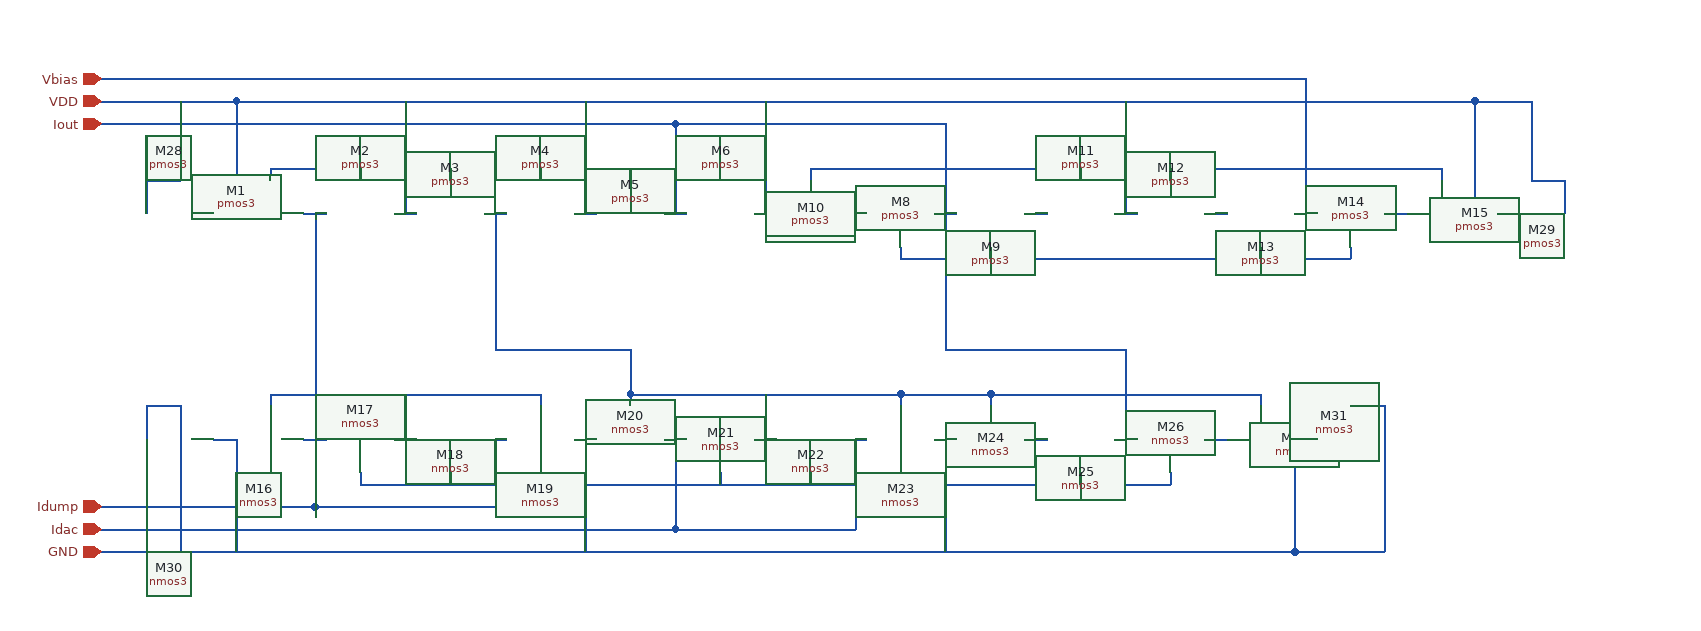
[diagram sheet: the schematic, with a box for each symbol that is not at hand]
v {xschem version=3.4.3 file_version=1.2
}
G {}
K {}
V {}
S {}
E {}
N 60 0 80 0 {
lab=#net1}
N 140 -0 160 -0 {
lab=VDD}
N 220 0 240 -0 {
lab=#net2}
N 300 0 320 0 {
lab=VDD}
N 380 -0 400 0 {
lab=Iout}
N 460 0 480 0 {
lab=VDD}
N 540 0 560 0 {
lab=#net3}
N 620 0 640 0 {
lab=Iout}
N 700 0 720 0 {
lab=#net4}
N 780 0 800 0 {
lab=VDD}
N 860 0 880 0 {
lab=#net5}
N 940 0 960 0 {
lab=VDD}
N 1020 0 1040 0 {
lab=#net6}
N 0 -100 0 0 {
lab=VDD}
N 1100 -100 1100 0 {
lab=VDD}
N 150 -100 150 -0 {
lab=VDD}
N 310 -100 310 -0 {
lab=VDD}
N 470 -100 470 0 {
lab=VDD}
N 790 -100 790 0 {
lab=VDD}
N -0 -100 1100 -100 {
lab=VDD}
N 30 -40 30 -30 {
lab=#net7}
N 510 -40 510 -30 {
lab=#net8}
N 430 -40 430 -30 {
lab=#net7}
N 350 -40 350 -30 {
lab=#net7}
N 270 -40 270 -30 {
lab=#net7}
N 190 -40 190 -30 {
lab=#net7}
N 110 -40 110 -30 {
lab=#net7}
N 590 30 590 40 {
lab=#net9}
N 590 40 990 40 {
lab=#net9}
N 990 30 990 40 {
lab=#net9}
N 910 30 910 40 {
lab=#net9}
N 670 30 670 40 {
lab=#net9}
N 830 -40 830 -30 {
lab=#net8}
N 30 -40 430 -40 {
lab=#net7}
N 1070 -40 1070 -30 {
lab=#net8}
N 750 -40 750 -30 {
lab=#net8}
N 510 -40 1070 -40 {
lab=#net8}
N 70 0 70 100 {
lab=#net1}
N 230 0 230 100 {
lab=#net2}
N 390 -80 390 -0 {
lab=Iout}
N 390 -80 630 -80 {
lab=Iout}
N 630 -80 630 0 {
lab=Iout}
N 950 -120 950 -0 {
lab=VDD}
N -20 -120 950 -120 {
lab=VDD}
N 30 160 30 170 {
lab=#net1}
N 30 160 270 160 {
lab=#net1}
N 270 160 270 170 {
lab=#net1}
N 140 200 160 200 {
lab=#net1}
N 150 160 150 200 {
lab=#net1}
N 70 100 70 160 {
lab=#net1}
N 60 200 80 200 {
lab=Idump}
N 220 200 240 200 {
lab=Idump}
N 110 230 110 240 {
lab=#net10}
N 110 240 830 240 {
lab=#net10}
N 830 230 830 240 {
lab=#net10}
N 750 230 750 240 {
lab=#net10}
N 510 230 510 240 {
lab=#net10}
N 430 230 430 240 {
lab=#net10}
N 190 230 190 240 {
lab=#net10}
N 300 200 320 200 {
lab=GND}
N 380 200 400 200 {
lab=Idac}
N 460 200 480 200 {
lab=#net2}
N 540 200 560 200 {
lab=Idac}
N 620 200 640 200 {
lab=GND}
N 700 200 720 200 {
lab=#net11}
N 780 200 800 200 {
lab=Iout}
N 860 200 880 200 {
lab=#net12}
N 230 200 230 260 {
lab=Idump}
N 70 260 230 260 {
lab=Idump}
N 70 200 70 260 {
lab=Idump}
N -20 260 70 260 {
lab=Idump}
N 310 200 310 300 {
lab=GND}
N -0 200 0 300 {
lab=GND}
N 630 200 630 300 {
lab=GND}
N 940 200 940 300 {
lab=GND}
N -20 300 940 300 {
lab=GND}
N 350 160 350 170 {
lab=#net2}
N 350 160 590 160 {
lab=#net2}
N 590 160 590 170 {
lab=#net2}
N 670 160 670 170 {
lab=#net2}
N 670 160 910 160 {
lab=#net2}
N 910 160 910 170 {
lab=#net2}
N 230 100 230 120 {
lab=#net2}
N 230 120 350 120 {
lab=#net2}
N 350 120 350 160 {
lab=#net2}
N 590 160 670 160 {
lab=#net2}
N 630 0 630 120 {
lab=Iout}
N 630 120 790 120 {
lab=Iout}
N 790 120 790 200 {
lab=Iout}
N 470 160 470 200 {
lab=#net2}
N 390 200 390 280 {
lab=Idac}
N 390 280 550 280 {
lab=Idac}
N 550 200 550 280 {
lab=Idac}
N -20 280 390 280 {
lab=Idac}
N -20 200 -0 200 {
lab=GND}
N -80 170 -50 170 {
lab=GND}
N -80 170 -80 200 {
lab=GND}
N -80 -30 -50 -30 {
lab=VDD}
N -80 -30 -80 0 {
lab=VDD}
N -20 0 0 -0 {
lab=VDD}
N -50 -120 -20 -120 {
lab=VDD}
N -120 -120 -50 -120 {
lab=VDD}
N -120 300 -20 300 {
lab=GND}
N -50 170 -50 300 {
lab=GND}
N -120 280 -20 280 {
lab=Idac}
N -120 260 -20 260 {
lab=Idump}
N -120 -100 0 -100 {
lab=VDD}
N -50 -100 -50 -30 {
lab=VDD}
N 1100 -100 1150 -100 {
lab=VDD}
N 1150 -100 1150 -30 {
lab=VDD}
N 1150 -30 1180 -30 {
lab=VDD}
N 1180 -30 1180 0 {
lab=VDD}
N 1100 0 1120 0 {
lab=VDD}
N 940 200 960 200 {
lab=GND}
N 990 170 1020 170 {
lab=GND}
N 1020 170 1020 200 {
lab=GND}
N 1020 200 1020 300 {
lab=GND}
N 940 300 1020 300 {
lab=GND}
N -120 -80 390 -80 {
lab=Iout}
C {madvlsi/pmos3.sym} 30 0 1 0 {name=M1
L=0.5
W=6
body=VDD
nf=1
mult=1
ad="'int((nf+1)/2) * W/nf * 0.29'" 
pd="'2*int((nf+1)/2) * (W/nf + 0.29)'"
as="'int((nf+2)/2) * W/nf * 0.29'" 
ps="'2*int((nf+2)/2) * (W/nf + 0.29)'"
nrd="'0.29 / W'" nrs="'0.29 / W'"
sa=0 sb=0 sd=0
model=pfet_01v8
spiceprefix=X
}
C {madvlsi/pmos3.sym} 110 0 1 0 {name=M2
L=0.5
W=6
body=VDD
nf=1
mult=1
ad="'int((nf+1)/2) * W/nf * 0.29'" 
pd="'2*int((nf+1)/2) * (W/nf + 0.29)'"
as="'int((nf+2)/2) * W/nf * 0.29'" 
ps="'2*int((nf+2)/2) * (W/nf + 0.29)'"
nrd="'0.29 / W'" nrs="'0.29 / W'"
sa=0 sb=0 sd=0
model=pfet_01v8
spiceprefix=X
}
C {madvlsi/pmos3.sym} 190 0 1 0 {name=M3
L=0.5
W=6
body=VDD
nf=1
mult=1
ad="'int((nf+1)/2) * W/nf * 0.29'" 
pd="'2*int((nf+1)/2) * (W/nf + 0.29)'"
as="'int((nf+2)/2) * W/nf * 0.29'" 
ps="'2*int((nf+2)/2) * (W/nf + 0.29)'"
nrd="'0.29 / W'" nrs="'0.29 / W'"
sa=0 sb=0 sd=0
model=pfet_01v8
spiceprefix=X
}
C {madvlsi/pmos3.sym} 270 0 1 0 {name=M4
L=0.5
W=6
body=VDD
nf=1
mult=1
ad="'int((nf+1)/2) * W/nf * 0.29'" 
pd="'2*int((nf+1)/2) * (W/nf + 0.29)'"
as="'int((nf+2)/2) * W/nf * 0.29'" 
ps="'2*int((nf+2)/2) * (W/nf + 0.29)'"
nrd="'0.29 / W'" nrs="'0.29 / W'"
sa=0 sb=0 sd=0
model=pfet_01v8
spiceprefix=X
}
C {madvlsi/pmos3.sym} 350 0 1 0 {name=M5
L=0.5
W=6
body=VDD
nf=1
mult=1
ad="'int((nf+1)/2) * W/nf * 0.29'" 
pd="'2*int((nf+1)/2) * (W/nf + 0.29)'"
as="'int((nf+2)/2) * W/nf * 0.29'" 
ps="'2*int((nf+2)/2) * (W/nf + 0.29)'"
nrd="'0.29 / W'" nrs="'0.29 / W'"
sa=0 sb=0 sd=0
model=pfet_01v8
spiceprefix=X
}
C {madvlsi/pmos3.sym} 430 0 1 0 {name=M6
L=0.5
W=6
body=VDD
nf=1
mult=1
ad="'int((nf+1)/2) * W/nf * 0.29'" 
pd="'2*int((nf+1)/2) * (W/nf + 0.29)'"
as="'int((nf+2)/2) * W/nf * 0.29'" 
ps="'2*int((nf+2)/2) * (W/nf + 0.29)'"
nrd="'0.29 / W'" nrs="'0.29 / W'"
sa=0 sb=0 sd=0
model=pfet_01v8
spiceprefix=X
}
C {madvlsi/pmos3.sym} 510 0 1 0 {name=M7
L=0.5
W=6
body=VDD
nf=1
mult=1
ad="'int((nf+1)/2) * W/nf * 0.29'" 
pd="'2*int((nf+1)/2) * (W/nf + 0.29)'"
as="'int((nf+2)/2) * W/nf * 0.29'" 
ps="'2*int((nf+2)/2) * (W/nf + 0.29)'"
nrd="'0.29 / W'" nrs="'0.29 / W'"
sa=0 sb=0 sd=0
model=pfet_01v8
spiceprefix=X
}
C {madvlsi/pmos3.sym} 590 0 3 0 {name=M8
L=0.5
W=6
body=VDD
nf=1
mult=1
ad="'int((nf+1)/2) * W/nf * 0.29'" 
pd="'2*int((nf+1)/2) * (W/nf + 0.29)'"
as="'int((nf+2)/2) * W/nf * 0.29'" 
ps="'2*int((nf+2)/2) * (W/nf + 0.29)'"
nrd="'0.29 / W'" nrs="'0.29 / W'"
sa=0 sb=0 sd=0
model=pfet_01v8
spiceprefix=X
}
C {madvlsi/pmos3.sym} 670 0 3 0 {name=M9
L=0.5
W=6
body=VDD
nf=1
mult=1
ad="'int((nf+1)/2) * W/nf * 0.29'" 
pd="'2*int((nf+1)/2) * (W/nf + 0.29)'"
as="'int((nf+2)/2) * W/nf * 0.29'" 
ps="'2*int((nf+2)/2) * (W/nf + 0.29)'"
nrd="'0.29 / W'" nrs="'0.29 / W'"
sa=0 sb=0 sd=0
model=pfet_01v8
spiceprefix=X
}
C {madvlsi/pmos3.sym} 510 0 1 0 {name=M10
L=0.5
W=6
body=VDD
nf=1
mult=1
ad="'int((nf+1)/2) * W/nf * 0.29'" 
pd="'2*int((nf+1)/2) * (W/nf + 0.29)'"
as="'int((nf+2)/2) * W/nf * 0.29'" 
ps="'2*int((nf+2)/2) * (W/nf + 0.29)'"
nrd="'0.29 / W'" nrs="'0.29 / W'"
sa=0 sb=0 sd=0
model=pfet_01v8
spiceprefix=X
}
C {madvlsi/pmos3.sym} 750 0 1 0 {name=M11
L=0.5
W=6
body=VDD
nf=1
mult=1
ad="'int((nf+1)/2) * W/nf * 0.29'" 
pd="'2*int((nf+1)/2) * (W/nf + 0.29)'"
as="'int((nf+2)/2) * W/nf * 0.29'" 
ps="'2*int((nf+2)/2) * (W/nf + 0.29)'"
nrd="'0.29 / W'" nrs="'0.29 / W'"
sa=0 sb=0 sd=0
model=pfet_01v8
spiceprefix=X
}
C {madvlsi/pmos3.sym} 830 0 1 0 {name=M12
L=0.5
W=6
body=VDD
nf=1
mult=1
ad="'int((nf+1)/2) * W/nf * 0.29'" 
pd="'2*int((nf+1)/2) * (W/nf + 0.29)'"
as="'int((nf+2)/2) * W/nf * 0.29'" 
ps="'2*int((nf+2)/2) * (W/nf + 0.29)'"
nrd="'0.29 / W'" nrs="'0.29 / W'"
sa=0 sb=0 sd=0
model=pfet_01v8
spiceprefix=X
}
C {madvlsi/pmos3.sym} 910 0 3 0 {name=M13
L=0.5
W=6
body=VDD
nf=1
mult=1
ad="'int((nf+1)/2) * W/nf * 0.29'" 
pd="'2*int((nf+1)/2) * (W/nf + 0.29)'"
as="'int((nf+2)/2) * W/nf * 0.29'" 
ps="'2*int((nf+2)/2) * (W/nf + 0.29)'"
nrd="'0.29 / W'" nrs="'0.29 / W'"
sa=0 sb=0 sd=0
model=pfet_01v8
spiceprefix=X
}
C {madvlsi/pmos3.sym} 990 0 3 0 {name=M14
L=0.5
W=6
body=VDD
nf=1
mult=1
ad="'int((nf+1)/2) * W/nf * 0.29'" 
pd="'2*int((nf+1)/2) * (W/nf + 0.29)'"
as="'int((nf+2)/2) * W/nf * 0.29'" 
ps="'2*int((nf+2)/2) * (W/nf + 0.29)'"
nrd="'0.29 / W'" nrs="'0.29 / W'"
sa=0 sb=0 sd=0
model=pfet_01v8
spiceprefix=X
}
C {madvlsi/pmos3.sym} 1070 0 1 0 {name=M15
L=0.5
W=6
body=VDD
nf=1
mult=1
ad="'int((nf+1)/2) * W/nf * 0.29'" 
pd="'2*int((nf+1)/2) * (W/nf + 0.29)'"
as="'int((nf+2)/2) * W/nf * 0.29'" 
ps="'2*int((nf+2)/2) * (W/nf + 0.29)'"
nrd="'0.29 / W'" nrs="'0.29 / W'"
sa=0 sb=0 sd=0
model=pfet_01v8
spiceprefix=X
}
C {madvlsi/nmos3.sym} 30 200 1 0 {name=M16
L=0.5
W=6
body=GND
nf=1
mult=1
ad="'int((nf+1)/2) * W/nf * 0.29'" 
pd="'2*int((nf+1)/2) * (W/nf + 0.29)'"
as="'int((nf+2)/2) * W/nf * 0.29'" 
ps="'2*int((nf+2)/2) * (W/nf + 0.29)'"
nrd="'0.29 / W'" nrs="'0.29 / W'"
sa=0 sb=0 sd=0
model=nfet_01v8
spiceprefix=X
}
C {madvlsi/nmos3.sym} 110 200 3 0 {name=M17
L=0.5
W=6
body=GND
nf=1
mult=1
ad="'int((nf+1)/2) * W/nf * 0.29'" 
pd="'2*int((nf+1)/2) * (W/nf + 0.29)'"
as="'int((nf+2)/2) * W/nf * 0.29'" 
ps="'2*int((nf+2)/2) * (W/nf + 0.29)'"
nrd="'0.29 / W'" nrs="'0.29 / W'"
sa=0 sb=0 sd=0
model=nfet_01v8
spiceprefix=X
}
C {madvlsi/nmos3.sym} 190 200 3 0 {name=M18
L=0.5
W=6
body=GND
nf=1
mult=1
ad="'int((nf+1)/2) * W/nf * 0.29'" 
pd="'2*int((nf+1)/2) * (W/nf + 0.29)'"
as="'int((nf+2)/2) * W/nf * 0.29'" 
ps="'2*int((nf+2)/2) * (W/nf + 0.29)'"
nrd="'0.29 / W'" nrs="'0.29 / W'"
sa=0 sb=0 sd=0
model=nfet_01v8
spiceprefix=X
}
C {madvlsi/nmos3.sym} 270 200 1 0 {name=M19
L=0.5
W=6
body=GND
nf=1
mult=1
ad="'int((nf+1)/2) * W/nf * 0.29'" 
pd="'2*int((nf+1)/2) * (W/nf + 0.29)'"
as="'int((nf+2)/2) * W/nf * 0.29'" 
ps="'2*int((nf+2)/2) * (W/nf + 0.29)'"
nrd="'0.29 / W'" nrs="'0.29 / W'"
sa=0 sb=0 sd=0
model=nfet_01v8
spiceprefix=X
}
C {madvlsi/nmos3.sym} 350 200 1 0 {name=M20
L=0.5
W=6
body=GND
nf=1
mult=1
ad="'int((nf+1)/2) * W/nf * 0.29'" 
pd="'2*int((nf+1)/2) * (W/nf + 0.29)'"
as="'int((nf+2)/2) * W/nf * 0.29'" 
ps="'2*int((nf+2)/2) * (W/nf + 0.29)'"
nrd="'0.29 / W'" nrs="'0.29 / W'"
sa=0 sb=0 sd=0
model=nfet_01v8
spiceprefix=X
}
C {madvlsi/nmos3.sym} 430 200 3 0 {name=M21
L=0.5
W=6
body=GND
nf=1
mult=1
ad="'int((nf+1)/2) * W/nf * 0.29'" 
pd="'2*int((nf+1)/2) * (W/nf + 0.29)'"
as="'int((nf+2)/2) * W/nf * 0.29'" 
ps="'2*int((nf+2)/2) * (W/nf + 0.29)'"
nrd="'0.29 / W'" nrs="'0.29 / W'"
sa=0 sb=0 sd=0
model=nfet_01v8
spiceprefix=X
}
C {madvlsi/nmos3.sym} 510 200 3 0 {name=M22
L=0.5
W=6
body=GND
nf=1
mult=1
ad="'int((nf+1)/2) * W/nf * 0.29'" 
pd="'2*int((nf+1)/2) * (W/nf + 0.29)'"
as="'int((nf+2)/2) * W/nf * 0.29'" 
ps="'2*int((nf+2)/2) * (W/nf + 0.29)'"
nrd="'0.29 / W'" nrs="'0.29 / W'"
sa=0 sb=0 sd=0
model=nfet_01v8
spiceprefix=X
}
C {madvlsi/nmos3.sym} 590 200 1 0 {name=M23
L=0.5
W=6
body=GND
nf=1
mult=1
ad="'int((nf+1)/2) * W/nf * 0.29'" 
pd="'2*int((nf+1)/2) * (W/nf + 0.29)'"
as="'int((nf+2)/2) * W/nf * 0.29'" 
ps="'2*int((nf+2)/2) * (W/nf + 0.29)'"
nrd="'0.29 / W'" nrs="'0.29 / W'"
sa=0 sb=0 sd=0
model=nfet_01v8
spiceprefix=X
}
C {madvlsi/nmos3.sym} 670 200 1 0 {name=M24
L=0.5
W=6
body=GND
nf=1
mult=1
ad="'int((nf+1)/2) * W/nf * 0.29'" 
pd="'2*int((nf+1)/2) * (W/nf + 0.29)'"
as="'int((nf+2)/2) * W/nf * 0.29'" 
ps="'2*int((nf+2)/2) * (W/nf + 0.29)'"
nrd="'0.29 / W'" nrs="'0.29 / W'"
sa=0 sb=0 sd=0
model=nfet_01v8
spiceprefix=X
}
C {madvlsi/nmos3.sym} 750 200 3 0 {name=M25
L=0.5
W=6
body=GND
nf=1
mult=1
ad="'int((nf+1)/2) * W/nf * 0.29'" 
pd="'2*int((nf+1)/2) * (W/nf + 0.29)'"
as="'int((nf+2)/2) * W/nf * 0.29'" 
ps="'2*int((nf+2)/2) * (W/nf + 0.29)'"
nrd="'0.29 / W'" nrs="'0.29 / W'"
sa=0 sb=0 sd=0
model=nfet_01v8
spiceprefix=X
}
C {madvlsi/nmos3.sym} 830 200 3 0 {name=M26
L=0.5
W=6
body=GND
nf=1
mult=1
ad="'int((nf+1)/2) * W/nf * 0.29'" 
pd="'2*int((nf+1)/2) * (W/nf + 0.29)'"
as="'int((nf+2)/2) * W/nf * 0.29'" 
ps="'2*int((nf+2)/2) * (W/nf + 0.29)'"
nrd="'0.29 / W'" nrs="'0.29 / W'"
sa=0 sb=0 sd=0
model=nfet_01v8
spiceprefix=X
}
C {madvlsi/nmos3.sym} 910 200 1 0 {name=M27
L=0.5
W=6
body=GND
nf=1
mult=1
ad="'int((nf+1)/2) * W/nf * 0.29'" 
pd="'2*int((nf+1)/2) * (W/nf + 0.29)'"
as="'int((nf+2)/2) * W/nf * 0.29'" 
ps="'2*int((nf+2)/2) * (W/nf + 0.29)'"
nrd="'0.29 / W'" nrs="'0.29 / W'"
sa=0 sb=0 sd=0
model=nfet_01v8
spiceprefix=X
}
C {madvlsi/pmos3.sym} -50 0 1 0 {name=M28
L=0.5
W=6
body=VDD
nf=1
mult=1
ad="'int((nf+1)/2) * W/nf * 0.29'" 
pd="'2*int((nf+1)/2) * (W/nf + 0.29)'"
as="'int((nf+2)/2) * W/nf * 0.29'" 
ps="'2*int((nf+2)/2) * (W/nf + 0.29)'"
nrd="'0.29 / W'" nrs="'0.29 / W'"
sa=0 sb=0 sd=0
model=pfet_01v8
spiceprefix=X
}
C {madvlsi/pmos3.sym} 1150 0 1 0 {name=M29
L=0.5
W=6
body=VDD
nf=1
mult=1
ad="'int((nf+1)/2) * W/nf * 0.29'" 
pd="'2*int((nf+1)/2) * (W/nf + 0.29)'"
as="'int((nf+2)/2) * W/nf * 0.29'" 
ps="'2*int((nf+2)/2) * (W/nf + 0.29)'"
nrd="'0.29 / W'" nrs="'0.29 / W'"
sa=0 sb=0 sd=0
model=pfet_01v8
spiceprefix=X
}
C {madvlsi/nmos3.sym} -50 200 1 0 {name=M30
L=0.5
W=6
body=GND
nf=1
mult=1
ad="'int((nf+1)/2) * W/nf * 0.29'" 
pd="'2*int((nf+1)/2) * (W/nf + 0.29)'"
as="'int((nf+2)/2) * W/nf * 0.29'" 
ps="'2*int((nf+2)/2) * (W/nf + 0.29)'"
nrd="'0.29 / W'" nrs="'0.29 / W'"
sa=0 sb=0 sd=0
model=nfet_01v8
spiceprefix=X
}
C {madvlsi/nmos3.sym} 990 200 1 0 {name=M31
L=0.5
W=6
body=GND
nf=1
mult=1
ad="'int((nf+1)/2) * W/nf * 0.29'" 
pd="'2*int((nf+1)/2) * (W/nf + 0.29)'"
as="'int((nf+2)/2) * W/nf * 0.29'" 
ps="'2*int((nf+2)/2) * (W/nf + 0.29)'"
nrd="'0.29 / W'" nrs="'0.29 / W'"
sa=0 sb=0 sd=0
model=nfet_01v8
spiceprefix=X
}
C {devices/iopin.sym} -120 -100 2 0 {name=p1 lab=VDD
L=0.5
W=6}
C {devices/ipin.sym} -120 260 0 0 {name=p4 lab=Idump
L=0.5
W=6}
C {devices/iopin.sym} -120 -80 2 0 {name=p2 lab=Iout
L=0.5
W=6}
C {devices/ipin.sym} -120 280 0 0 {name=p3 lab=Idac
L=0.5
W=6}
C {devices/iopin.sym} -120 300 2 0 {name=p5 lab=GND
L=0.5
W=6}
C {devices/iopin.sym} -120 -120 2 0 {name=p6 lab=Vbias
L=0.5
W=6}
